VERSION 5.7 ;
BUSBITCHARS "[]" ;
DIVIDERCHAR "/" ;
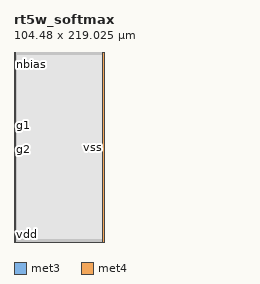
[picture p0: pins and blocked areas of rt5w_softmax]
MACRO rt5w_softmax
  CLASS BLOCK ;
  FOREIGN rt5w_softmax ;
  ORIGIN 3.050 218.225 ;
  SIZE 104.480 BY 219.025 ;
  SYMMETRY X Y ;
  PIN g0
    DIRECTION INOUT ;
    USE SIGNAL ;
    PORT
      LAYER met3 ;
        RECT -3.050 -17.395 -0.550 -17.095 ;
    END
  END g0
  PIN g1
    DIRECTION INOUT ;
    USE SIGNAL ;
    PORT
      LAYER met3 ;
        RECT -3.050 -84.055 -0.550 -83.755 ;
    END
  END g1
  PIN g2
    DIRECTION INOUT ;
    USE SIGNAL ;
    PORT
      LAYER met3 ;
        RECT -3.050 -112.105 -0.550 -111.805 ;
    END
  END g2
  PIN g3
    DIRECTION INOUT ;
    USE SIGNAL ;
    PORT
      LAYER met3 ;
        RECT -3.050 -109.385 -0.550 -109.085 ;
    END
  END g3
  PIN kbias
    DIRECTION INOUT ;
    USE SIGNAL ;
    PORT
      LAYER met3 ;
        RECT -3.050 -18.755 -0.550 -18.455 ;
    END
  END kbias
  PIN nbias
    DIRECTION INOUT ;
    USE SIGNAL ;
    PORT
      LAYER met3 ;
        RECT -3.050 -13.995 -0.550 -13.695 ;
    END
  END nbias
  PIN out0
    DIRECTION INOUT ;
    USE SIGNAL ;
    PORT
      LAYER met3 ;
        RECT -3.050 -18.075 -0.550 -17.775 ;
    END
  END out0
  PIN out1
    DIRECTION INOUT ;
    USE SIGNAL ;
    PORT
      LAYER met3 ;
        RECT -3.050 -12.635 -0.550 -12.335 ;
    END
  END out1
  PIN out2
    DIRECTION INOUT ;
    USE SIGNAL ;
    PORT
      LAYER met3 ;
        RECT -3.050 -16.035 -0.550 -15.735 ;
    END
  END out2
  PIN out3
    DIRECTION INOUT ;
    USE SIGNAL ;
    PORT
      LAYER met3 ;
        RECT -3.050 -11.955 -0.550 -11.655 ;
    END
  END out3
  PIN vb
    DIRECTION INOUT ;
    USE SIGNAL ;
    PORT
      LAYER met3 ;
        RECT -3.050 -16.715 -0.550 -16.415 ;
    END
  END vb
  PIN vcas
    DIRECTION INOUT ;
    USE SIGNAL ;
    PORT
      LAYER met3 ;
        RECT -3.050 -13.315 -0.550 -13.015 ;
    END
  END vcas
  PIN vdd
    DIRECTION INOUT ;
    USE SIGNAL ;
    PORT
      LAYER met4 ;
        RECT -2.400 -218.225 -0.800 0.800 ;
    END
  END vdd
  PIN vr
    DIRECTION INOUT ;
    USE SIGNAL ;
    PORT
      LAYER met3 ;
        RECT -3.050 -14.675 -0.550 -14.375 ;
    END
  END vr
  PIN vss
    DIRECTION INOUT ;
    USE SIGNAL ;
    PORT
      LAYER met4 ;
        RECT 99.180 -218.225 100.780 0.800 ;
    END
  END vss
  OBS
    LAYER li1 ;
      RECT -0.055 -217.140 89.835 -216.810 ;
      RECT -0.655 -98.045 -0.550 -97.715 ;
      RECT -0.655 -65.805 -0.550 -65.475 ;
      RECT -0.655 -193.850 -0.550 -193.520 ;
      RECT -0.655 -170.560 -0.550 -170.230 ;
      RECT -0.655 -31.315 -0.550 -30.985 ;
      RECT -0.550 -215.725 98.930 -1.700 ;
      RECT -0.655 -146.580 -0.550 -146.250 ;
      RECT -0.655 -125.345 -0.550 -125.015 ;
      RECT -0.655 -0.615 89.235 -0.285 ;
    LAYER met1 ;
      RECT -0.100 -217.140 89.880 -216.810 ;
      RECT -0.700 -98.045 -0.550 -97.715 ;
      RECT -0.700 -65.805 -0.550 -65.475 ;
      RECT -0.700 -193.850 -0.550 -193.520 ;
      RECT -0.700 -170.560 -0.550 -170.230 ;
      RECT -0.700 -31.315 -0.550 -30.985 ;
      RECT -0.550 -215.725 98.930 -1.700 ;
      RECT -0.700 -146.580 -0.550 -146.250 ;
      RECT -0.700 -125.345 -0.550 -125.015 ;
      RECT -0.700 -0.615 89.280 -0.285 ;
    LAYER met2 ;
      RECT -0.040 -217.160 0.240 -216.790 ;
      RECT 89.540 -217.160 89.820 -216.790 ;
      RECT -0.640 -0.635 -0.360 -0.265 ;
      RECT 5.335 -216.790 5.535 -215.725 ;
      RECT 5.295 -217.160 5.575 -216.790 ;
      RECT 13.915 -216.790 14.115 -215.725 ;
      RECT 13.875 -217.160 14.155 -216.790 ;
      RECT 22.495 -216.790 22.695 -215.725 ;
      RECT 22.455 -217.160 22.735 -216.790 ;
      RECT 31.075 -216.790 31.275 -215.725 ;
      RECT 31.035 -217.160 31.315 -216.790 ;
      RECT 39.655 -216.790 39.855 -215.725 ;
      RECT 39.615 -217.160 39.895 -216.790 ;
      RECT 48.235 -216.790 48.435 -215.725 ;
      RECT 48.195 -217.160 48.475 -216.790 ;
      RECT 58.505 -216.790 58.705 -215.725 ;
      RECT 58.465 -217.160 58.745 -216.790 ;
      RECT 67.085 -216.790 67.285 -215.725 ;
      RECT 67.045 -217.160 67.325 -216.790 ;
      RECT 75.665 -216.790 75.865 -215.725 ;
      RECT 75.625 -217.160 75.905 -216.790 ;
      RECT 4.695 -0.635 4.975 -0.265 ;
      RECT 4.735 -1.700 4.935 -0.635 ;
      RECT 13.275 -0.635 13.555 -0.265 ;
      RECT 13.315 -1.700 13.515 -0.635 ;
      RECT 21.855 -0.635 22.135 -0.265 ;
      RECT 21.895 -1.700 22.095 -0.635 ;
      RECT 30.435 -0.635 30.715 -0.265 ;
      RECT 30.475 -1.700 30.675 -0.635 ;
      RECT 39.015 -0.635 39.295 -0.265 ;
      RECT 39.055 -1.700 39.255 -0.635 ;
      RECT 47.595 -0.635 47.875 -0.265 ;
      RECT 47.635 -1.700 47.835 -0.635 ;
      RECT 57.865 -0.635 58.145 -0.265 ;
      RECT 57.905 -1.700 58.105 -0.635 ;
      RECT 66.445 -0.635 66.725 -0.265 ;
      RECT 66.485 -1.700 66.685 -0.635 ;
      RECT 75.025 -0.635 75.305 -0.265 ;
      RECT 75.065 -1.700 75.265 -0.635 ;
      RECT -0.640 -98.065 -0.550 -97.695 ;
      RECT 83.605 -0.635 83.885 -0.265 ;
      RECT 83.645 -1.700 83.845 -0.635 ;
      RECT -0.640 -52.570 -0.600 -52.200 ;
      RECT -0.630 -31.310 -0.550 -30.990 ;
      RECT -0.600 -65.480 -0.550 -31.310 ;
      RECT -0.630 -65.800 -0.550 -65.480 ;
      RECT -0.640 -193.870 -0.550 -193.500 ;
      RECT -0.640 -170.580 -0.550 -170.210 ;
      RECT -0.550 -215.725 98.930 -1.700 ;
      RECT 84.245 -216.790 84.445 -215.725 ;
      RECT 84.205 -217.160 84.485 -216.790 ;
      RECT -0.630 -125.340 -0.550 -125.020 ;
      RECT -0.600 -146.230 -0.550 -125.340 ;
      RECT -0.640 -146.600 -0.550 -146.230 ;
      RECT 88.940 -0.635 89.220 -0.265 ;
    LAYER met3 ;
      RECT -3.050 -217.425 101.430 -216.525 ;
      RECT -0.550 -51.935 98.930 -1.700 ;
      RECT -3.050 -52.835 101.430 -51.935 ;
      RECT -0.550 -97.430 98.930 -52.835 ;
      RECT -3.050 -98.330 101.430 -97.430 ;
      RECT -0.550 -145.965 98.930 -98.330 ;
      RECT -3.050 -146.865 101.430 -145.965 ;
      RECT -0.550 -169.945 98.930 -146.865 ;
      RECT -3.050 -170.845 101.430 -169.945 ;
      RECT -0.550 -193.235 98.930 -170.845 ;
      RECT -3.050 -194.135 101.430 -193.235 ;
      RECT -0.550 -215.725 98.930 -194.135 ;
      RECT -3.050 -0.900 101.430 0.000 ;
    LAYER met4 ;
      RECT -0.550 -215.725 98.930 -1.700 ;
  END
END rt5w_softmax
END LIBRARY
